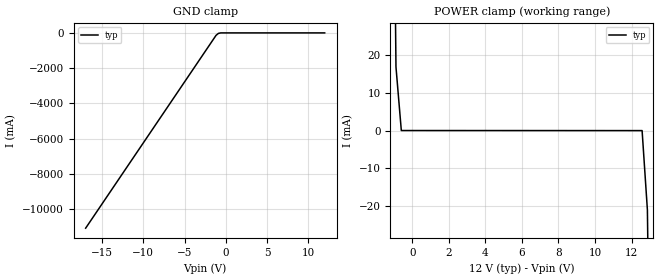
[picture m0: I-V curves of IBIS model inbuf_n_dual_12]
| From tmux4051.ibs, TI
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| inbuf_n_dual_12
[Model]   inbuf_n_dual_12
Model_type   Input
Vinl = 0.8
Vinh = 1.35
|   typ   min   max
C_comp   1.598234e-12   NA   NA
[Voltage Range]   12   NA   NA
[Temperature Range]   27   NA   NA
[Power Clamp Reference]   12   NA   NA
[GND Clamp Reference]   0   NA   NA
[GND Clamp]
|   Voltage   I(typ)   I(min)   I(max)
-17V      -11.08A    NA         NA
-1.182V   -139.8mA   NA         NA
-888.9mV  -26.42mA   NA         NA
-596mV    -31.07uA   NA         NA
12V       66.66nA    NA         NA
[POWER Clamp]
|   Voltage   I(typ)   I(min)   I(max)
-5V       3.679A     NA         NA
-1.192V   156.9mA    NA         NA
-899mV    16.91mA    NA         NA
-606.1mV  1.603uA    NA         NA
12.58V    -17.94uA   NA         NA
12.87V    -21.13mA   NA         NA
13.16V    -130.5mA   NA         NA
24V       -7.582A    NA         NA
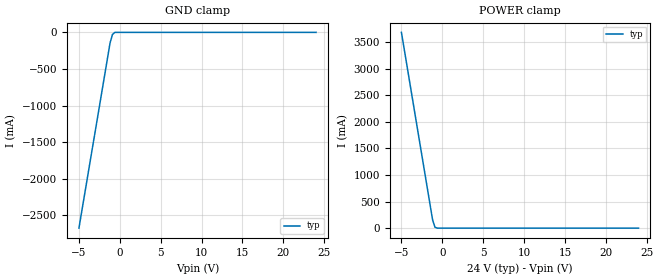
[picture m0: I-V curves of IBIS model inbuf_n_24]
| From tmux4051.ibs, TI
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| inbuf_n_24
[Model]   inbuf_n_24
Model_type   Input
Vinl = 0.8
Vinh = 1.35
|   typ   min   max
C_comp   4.014581e-13   NA   NA
[Voltage Range]   24   NA   NA
[Temperature Range]   27   NA   NA
[Power Clamp Reference]   24   NA   NA
[GND Clamp Reference]   0   NA   NA
[GND Clamp]
|   Voltage   I(typ)   I(min)   I(max)
-5V       -2.674A    NA         NA
-1.192V   -144.8mA   NA         NA
-899mV    -29.34mA   NA         NA
-606.1mV  -41.8uA    NA         NA
24V       67.16nA    NA         NA
[POWER Clamp]
|   Voltage   I(typ)   I(min)   I(max)
-5V       3.679A     NA         NA
-1.192V   156.9mA    NA         NA
-899mV    16.91mA    NA         NA
-606.1mV  1.603uA    NA         NA
24V       -416.6nA   NA         NA
